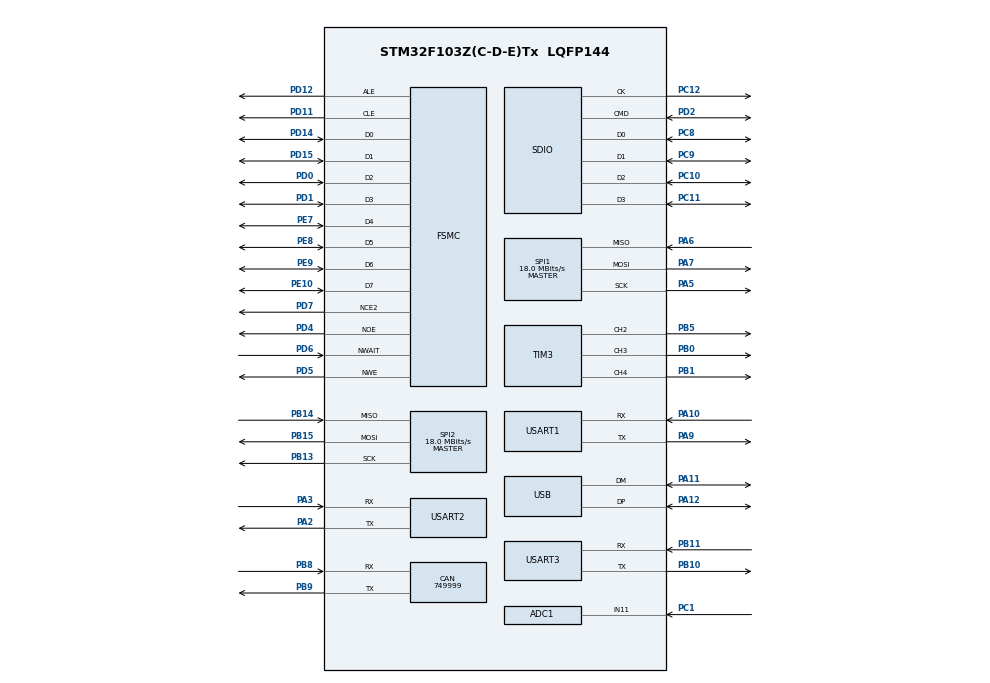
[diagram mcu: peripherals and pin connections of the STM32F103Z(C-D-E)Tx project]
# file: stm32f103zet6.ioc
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ADC1.Channel-0\#ChannelRegularConversion=ADC_CHANNEL_11
ADC1.NbrOfConversionFlag=1
ADC1.Rank-0\#ChannelRegularConversion=1
ADC1.SamplingTime-0\#ChannelRegularConversion=ADC_SAMPLETIME_1CYCLE_5
ADC1.master=1
CAN.CalculateBaudRate=749999
CAN.CalculateTimeBit=1333
CAN.CalculateTimeQuantum=444.44444444444446
FSMC.AttributeSpaceHiZSetupTime1=4
FSMC.AttributeSpaceHoldSetupTime1=2
FSMC.AttributeSpaceSetupTime1=4
FSMC.AttributeSpaceWaitSetupTime1=3
FSMC.CommonSpaceHiZSetupTime1=4
FSMC.CommonSpaceHoldSetupTime1=2
FSMC.CommonSpaceSetupTime1=4
FSMC.CommonSpaceWaitSetupTime1=3
FSMC.ECCPageSize1=FSMC_NAND_ECC_PAGE_SIZE_512BYTE
FSMC.EccComputation1=FSMC_NAND_ECC_ENABLE
FSMC.NandBlockNbr1=1024
FSMC.NandBlockSize1=64
FSMC.NandPageSize1=2048
FSMC.NandPlaneNbr1=1024
FSMC.NandPlaneSize1=1024
FSMC.NandSpareAreaSize1=64
Mcu.Family=STM32F1
Mcu.Name=STM32F103Z(C-D-E)Tx
Mcu.Package=LQFP144
NVIC.PriorityGroup=NVIC_PRIORITYGROUP_4
NVIC.USART1_IRQn=true\:0\:0\:false\:false\:true\:true\:true
OSC_IN.Mode=HSE-External-Oscillator
OSC_IN.Signal=RCC_OSC_IN
OSC_OUT.Mode=HSE-External-Oscillator
OSC_OUT.Signal=RCC_OSC_OUT
PA10.Mode=Asynchronous
PA10.Signal=USART1_RX
PA11.Mode=Device
PA11.Signal=USB_DM
PA12.Mode=Device
PA12.Signal=USB_DP
PA13.Mode=Serial_Wire
PA13.Signal=SYS_JTMS-SWDIO
PA14.Mode=Serial_Wire
PA14.Signal=SYS_JTCK-SWCLK
PA2.Mode=Asynchronous
PA2.Signal=USART2_TX
PA3.Mode=Asynchronous
PA3.Signal=USART2_RX
PA5.Mode=Full_Duplex_Master
PA5.Signal=SPI1_SCK
PA6.Mode=Full_Duplex_Master
PA6.Signal=SPI1_MISO
PA7.Mode=Full_Duplex_Master
PA7.Signal=SPI1_MOSI
PA9.Mode=Asynchronous
PA9.Signal=USART1_TX
PB0.Signal=S_TIM3_CH3
PB1.Signal=S_TIM3_CH4
PB10.Mode=Asynchronous
PB10.Signal=USART3_TX
PB11.Mode=Asynchronous
PB11.Signal=USART3_RX
PB13.Mode=Full_Duplex_Master
PB13.Signal=SPI2_SCK
PB14.Mode=Full_Duplex_Master
PB14.Signal=SPI2_MISO
PB15.Mode=Full_Duplex_Master
PB15.Signal=SPI2_MOSI
PB5.Signal=S_TIM3_CH2
PB8.Mode=CAN_Activate
PB8.Signal=CAN_RX
PB9.Mode=CAN_Activate
PB9.Signal=CAN_TX
PC1.Signal=ADCx_IN11
PC10.Mode=SD_4_bits_Wide_bus
PC10.Signal=SDIO_D2
PC11.Mode=SD_4_bits_Wide_bus
PC11.Signal=SDIO_D3
PC12.Mode=SD_4_bits_Wide_bus
PC12.Signal=SDIO_CK
PC14-OSC32_IN.Mode=LSE-External-Oscillator
PC14-OSC32_IN.Signal=RCC_OSC32_IN
PC15-OSC32_OUT.Mode=LSE-External-Oscillator
PC15-OSC32_OUT.Signal=RCC_OSC32_OUT
PC8.Mode=SD_4_bits_Wide_bus
PC8.Signal=SDIO_D0
PC9.Mode=SD_4_bits_Wide_bus
PC9.Signal=SDIO_D1
PD0.Signal=FSMC_D2_DA2
PD1.Signal=FSMC_D3_DA3
PD11.Signal=FSMC_A16_CLE
PD12.Signal=FSMC_A17_ALE
PD14.Signal=FSMC_D0_DA0
PD15.Signal=FSMC_D1_DA1
PD2.Mode=SD_4_bits_Wide_bus
PD2.Signal=SDIO_CMD
PD4.Signal=FSMC_NOE
PD5.Signal=FSMC_NWE
PD6.Signal=FSMC_NWAIT
PD7.Mode=NandChipSelect2_1
PD7.Signal=FSMC_NCE2
PE10.Signal=FSMC_D7_DA7
PE7.Signal=FSMC_D4_DA4
PE8.Signal=FSMC_D5_DA5
PE9.Signal=FSMC_D6_DA6
ProjectManager.HeapSize=0x200
ProjectManager.StackSize=0x400
ProjectManager.TargetToolchain=MDK-ARM V5
RCC.ADCPresc=RCC_ADCPCLK2_DIV6
RCC.AHBFreq_Value=72000000
RCC.APB1CLKDivider=RCC_HCLK_DIV2
RCC.APB1Freq_Value=36000000
RCC.APB1TimFreq_Value=72000000
RCC.APB2Freq_Value=72000000
RCC.APB2TimFreq_Value=72000000
RCC.HCLKFreq_Value=72000000
RCC.PLLMUL=RCC_PLL_MUL9
RCC.PLLSourceVirtual=RCC_PLLSOURCE_HSE
RCC.SYSCLKFreq_VALUE=72000000
RCC.SYSCLKSource=RCC_SYSCLKSOURCE_PLLCLK
RCC.USBFreq_Value=48000000
RCC.USBPrescaler=RCC_USBCLKSOURCE_PLL_DIV1_5
SH.ADCx_IN11.0=ADC1_IN11,IN11
SH.FSMC_A16_CLE.0=FSMC_CLE,8b-dmux1
SH.FSMC_A17_ALE.0=FSMC_ALE,8b-dmux1
SH.FSMC_D0_DA0.0=FSMC_D0,8b-dmux1
SH.FSMC_D1_DA1.0=FSMC_D1,8b-dmux1
SH.FSMC_D2_DA2.0=FSMC_D2,8b-dmux1
SH.FSMC_D3_DA3.0=FSMC_D3,8b-dmux1
SH.FSMC_D4_DA4.0=FSMC_D4,8b-dmux1
SH.FSMC_D5_DA5.0=FSMC_D5,8b-dmux1
SH.FSMC_D6_DA6.0=FSMC_D6,8b-dmux1
SH.FSMC_D7_DA7.0=FSMC_D7,8b-dmux1
SH.FSMC_NOE.0=FSMC_NOE,8b-dmux1
SH.FSMC_NWAIT.0=FSMC_NWAIT,Wait1
SH.FSMC_NWE.0=FSMC_NWE,8b-dmux1
SH.S_TIM3_CH2.0=TIM3_CH2,PWM Generation2 CH2
SH.S_TIM3_CH3.0=TIM3_CH3,PWM Generation3 CH3
SH.S_TIM3_CH4.0=TIM3_CH4,PWM Generation4 CH4
SPI1.BaudRatePrescaler=SPI_BAUDRATEPRESCALER_4
SPI1.CalculateBaudRate=18.0 MBits/s
SPI1.Direction=SPI_DIRECTION_2LINES
SPI1.Mode=SPI_MODE_MASTER
SPI1.VirtualType=VM_MASTER
SPI2.CalculateBaudRate=18.0 MBits/s
SPI2.Direction=SPI_DIRECTION_2LINES
SPI2.Mode=SPI_MODE_MASTER
SPI2.VirtualType=VM_MASTER
TIM3.Channel-PWM\ Generation2\ CH2=TIM_CHANNEL_2
TIM3.Channel-PWM\ Generation3\ CH3=TIM_CHANNEL_3
TIM3.Channel-PWM\ Generation4\ CH4=TIM_CHANNEL_4
USART1.VirtualMode=VM_ASYNC
USART2.VirtualMode=VM_ASYNC
USART3.VirtualMode=VM_ASYNC
VP_IWDG_VS_IWDG.Mode=IWDG_Activate
VP_RTC_VS_RTC_Activate.Mode=RTC_Enabled
VP_TIM2_VS_ClockSourceINT.Mode=Internal
VP_TIM3_VS_ClockSourceINT.Mode=Internal
VP_TIM4_VS_ClockSourceINT.Mode=Internal
VP_TIM5_VS_ClockSourceINT.Mode=Internal
board=custom

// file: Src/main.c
/* USER CODE BEGIN Header */
/**
  ******************************************************************************
  * @file           : main.c
  * @brief          : Main program body
  ******************************************************************************
  ** This notice applies to any and all portions of this file
  * that are not between comment pairs USER CODE BEGIN and
  * USER CODE END. Other portions of this file, whether
  * inserted by the user or by software development tools
  * are owned by their respective copyright owners.
  *
  * COPYRIGHT(c) 2018 STMicroelectronics
  *
  * Redistribution and use in source and binary forms, with or without modification,
  * are permitted provided that the following conditions are met:
  *   1. Redistributions of source code must retain the above copyright notice,
  *      this list of conditions and the following disclaimer.
  *   2. Redistributions in binary form must reproduce the above copyright notice,
  *      this list of conditions and the following disclaimer in the documentation
  *      and/or other materials provided with the distribution.
  *   3. Neither the name of STMicroelectronics nor the names of its contributors
  *      may be used to endorse or promote products derived from this software
  *      without specific prior written permission.
  *
  * THIS SOFTWARE IS PROVIDED BY THE COPYRIGHT HOLDERS AND CONTRIBUTORS "AS IS"
  * AND ANY EXPRESS OR IMPLIED WARRANTIES, INCLUDING, BUT NOT LIMITED TO, THE
  * IMPLIED WARRANTIES OF MERCHANTABILITY AND FITNESS FOR A PARTICULAR PURPOSE ARE
  * DISCLAIMED. IN NO EVENT SHALL THE COPYRIGHT HOLDER OR CONTRIBUTORS BE LIABLE
  * FOR ANY DIRECT, INDIRECT, INCIDENTAL, SPECIAL, EXEMPLARY, OR CONSEQUENTIAL
  * DAMAGES (INCLUDING, BUT NOT LIMITED TO, PROCUREMENT OF SUBSTITUTE GOODS OR
  * SERVICES; LOSS OF USE, DATA, OR PROFITS; OR BUSINESS INTERRUPTION) HOWEVER
  * CAUSED AND ON ANY THEORY OF LIABILITY, WHETHER IN CONTRACT, STRICT LIABILITY,
  * OR TORT (INCLUDING NEGLIGENCE OR OTHERWISE) ARISING IN ANY WAY OUT OF THE USE
  * OF THIS SOFTWARE, EVEN IF ADVISED OF THE POSSIBILITY OF SUCH DAMAGE.
  *
  ******************************************************************************
  */
/* USER CODE END Header */

#include "main.h"

ADC_HandleTypeDef hadc1;

CAN_HandleTypeDef hcan;

IWDG_HandleTypeDef hiwdg;

RTC_HandleTypeDef hrtc;

SD_HandleTypeDef hsd;

SPI_HandleTypeDef hspi1;
SPI_HandleTypeDef hspi2;

TIM_HandleTypeDef htim2;
TIM_HandleTypeDef htim3;
TIM_HandleTypeDef htim4;
TIM_HandleTypeDef htim5;

UART_HandleTypeDef huart1;
UART_HandleTypeDef huart2;
UART_HandleTypeDef huart3;

PCD_HandleTypeDef hpcd_USB_FS;

/* USER CODE BEGIN PV */
/* Private variables ---------------------------------------------------------*/

/* USER CODE END PV */

void SystemClock_Config(void);
static void MX_GPIO_Init(void);
static void MX_USART1_UART_Init(void);
static void MX_SPI2_Init(void);
static void MX_USART2_UART_Init(void);
static void MX_SPI1_Init(void);
static void MX_USART3_UART_Init(void);
static void MX_ADC1_Init(void);
static void MX_RTC_Init(void);
static void MX_IWDG_Init(void);
static void MX_TIM2_Init(void);
static void MX_TIM3_Init(void);
static void MX_TIM4_Init(void);
static void MX_TIM5_Init(void);
static void MX_SDIO_SD_Init(void);
static void MX_CAN_Init(void);
static void MX_USB_PCD_Init(void);
/* USER CODE BEGIN PFP */
/* Private function prototypes -----------------------------------------------*/

/* USER CODE END PFP */

int main(void)
{

  /* MCU Configuration--------------------------------------------------------*/

  /* Reset of all peripherals, Initializes the Flash interface and the Systick. */
  HAL_Init();

  /* Configure the system clock */
  SystemClock_Config();

  /* Initialize all configured peripherals */
  MX_GPIO_Init();
  MX_USART1_UART_Init();
  MX_SPI2_Init();
  MX_USART2_UART_Init();
  MX_SPI1_Init();
  MX_USART3_UART_Init();
  MX_ADC1_Init();
  MX_RTC_Init();
  MX_IWDG_Init();
  MX_TIM2_Init();
  MX_TIM3_Init();
  MX_TIM4_Init();
  MX_TIM5_Init();
  MX_SDIO_SD_Init();
  MX_CAN_Init();
  MX_USB_PCD_Init();

  /* Infinite loop */
  while (1)
  {

  }
}

void SystemClock_Config(void)
{
  RCC_OscInitTypeDef RCC_OscInitStruct = {0};
  RCC_ClkInitTypeDef RCC_ClkInitStruct = {0};
  RCC_PeriphCLKInitTypeDef PeriphClkInit = {0};

  /** Initializes the CPU, AHB and APB busses clocks
  */
  RCC_OscInitStruct.OscillatorType = RCC_OSCILLATORTYPE_LSI|RCC_OSCILLATORTYPE_HSE
                              |RCC_OSCILLATORTYPE_LSE;
  RCC_OscInitStruct.HSEState = RCC_HSE_ON;
  RCC_OscInitStruct.HSEPredivValue = RCC_HSE_PREDIV_DIV1;
  RCC_OscInitStruct.LSEState = RCC_LSE_ON;
  RCC_OscInitStruct.HSIState = RCC_HSI_ON;
  RCC_OscInitStruct.LSIState = RCC_LSI_ON;
  RCC_OscInitStruct.PLL.PLLState = RCC_PLL_ON;
  RCC_OscInitStruct.PLL.PLLSource = RCC_PLLSOURCE_HSE;
  RCC_OscInitStruct.PLL.PLLMUL = RCC_PLL_MUL6;
  if (HAL_RCC_OscConfig(&RCC_OscInitStruct) != HAL_OK)
  {
    Error_Handler();
  }
  /** Initializes the CPU, AHB and APB busses clocks
  */
  RCC_ClkInitStruct.ClockType = RCC_CLOCKTYPE_HCLK|RCC_CLOCKTYPE_SYSCLK
                              |RCC_CLOCKTYPE_PCLK1|RCC_CLOCKTYPE_PCLK2;
  RCC_ClkInitStruct.SYSCLKSource = RCC_SYSCLKSOURCE_PLLCLK;
  RCC_ClkInitStruct.AHBCLKDivider = RCC_SYSCLK_DIV1;
  RCC_ClkInitStruct.APB1CLKDivider = RCC_HCLK_DIV2;
  RCC_ClkInitStruct.APB2CLKDivider = RCC_HCLK_DIV1;

  if (HAL_RCC_ClockConfig(&RCC_ClkInitStruct, FLASH_LATENCY_1) != HAL_OK)
  {
    Error_Handler();
  }
  PeriphClkInit.PeriphClockSelection = RCC_PERIPHCLK_RTC|RCC_PERIPHCLK_ADC
                              |RCC_PERIPHCLK_USB;
  PeriphClkInit.RTCClockSelection = RCC_RTCCLKSOURCE_LSE;
  PeriphClkInit.AdcClockSelection = RCC_ADCPCLK2_DIV4;
  PeriphClkInit.UsbClockSelection = RCC_USBCLKSOURCE_PLL;
  if (HAL_RCCEx_PeriphCLKConfig(&PeriphClkInit) != HAL_OK)
  {
    Error_Handler();
  }
}

static void MX_ADC1_Init(void)
{

  ADC_ChannelConfTypeDef sConfig = {0};

  /** Common config
  */
  hadc1.Instance = ADC1;
  hadc1.Init.ScanConvMode = ADC_SCAN_DISABLE;
  hadc1.Init.ContinuousConvMode = DISABLE;
  hadc1.Init.DiscontinuousConvMode = DISABLE;
  hadc1.Init.ExternalTrigConv = ADC_SOFTWARE_START;
  hadc1.Init.DataAlign = ADC_DATAALIGN_RIGHT;
  hadc1.Init.NbrOfConversion = 1;
  if (HAL_ADC_Init(&hadc1) != HAL_OK)
  {
    Error_Handler();
  }
  /** Configure Regular Channel
  */
  sConfig.Channel = ADC_CHANNEL_11;
  sConfig.Rank = ADC_REGULAR_RANK_1;
  sConfig.SamplingTime = ADC_SAMPLETIME_1CYCLE_5;
  if (HAL_ADC_ConfigChannel(&hadc1, &sConfig) != HAL_OK)
  {
    Error_Handler();
  }

}

static void MX_CAN_Init(void)
{

  hcan.Instance = CAN1;
  hcan.Init.Prescaler = 16;
  hcan.Init.Mode = CAN_MODE_NORMAL;
  hcan.Init.SyncJumpWidth = CAN_SJW_1TQ;
  hcan.Init.TimeSeg1 = CAN_BS1_1TQ;
  hcan.Init.TimeSeg2 = CAN_BS2_1TQ;
  hcan.Init.TimeTriggeredMode = DISABLE;
  hcan.Init.AutoBusOff = DISABLE;
  hcan.Init.AutoWakeUp = DISABLE;
  hcan.Init.AutoRetransmission = DISABLE;
  hcan.Init.ReceiveFifoLocked = DISABLE;
  hcan.Init.TransmitFifoPriority = DISABLE;
  if (HAL_CAN_Init(&hcan) != HAL_OK)
  {
    Error_Handler();
  }

}

static void MX_IWDG_Init(void)
{

  hiwdg.Instance = IWDG;
  hiwdg.Init.Prescaler = IWDG_PRESCALER_4;
  hiwdg.Init.Reload = 4095;
  if (HAL_IWDG_Init(&hiwdg) != HAL_OK)
  {
    Error_Handler();
  }

}

static void MX_RTC_Init(void)
{

  /** Initialize RTC Only
  */
  hrtc.Instance = RTC;
  hrtc.Init.AsynchPrediv = RTC_AUTO_1_SECOND;
  hrtc.Init.OutPut = RTC_OUTPUTSOURCE_ALARM;
  if (HAL_RTC_Init(&hrtc) != HAL_OK)
  {
    Error_Handler();
  }

}

static void MX_SDIO_SD_Init(void)
{

  hsd.Instance = SDIO;
  hsd.Init.ClockEdge = SDIO_CLOCK_EDGE_RISING;
  hsd.Init.ClockBypass = SDIO_CLOCK_BYPASS_DISABLE;
  hsd.Init.ClockPowerSave = SDIO_CLOCK_POWER_SAVE_DISABLE;
  hsd.Init.BusWide = SDIO_BUS_WIDE_1B;
  hsd.Init.HardwareFlowControl = SDIO_HARDWARE_FLOW_CONTROL_DISABLE;
  hsd.Init.ClockDiv = 0;
  if (HAL_SD_Init(&hsd) != HAL_OK)
  {
    Error_Handler();
  }
  if (HAL_SD_ConfigWideBusOperation(&hsd, SDIO_BUS_WIDE_4B) != HAL_OK)
  {
    Error_Handler();
  }

}

static void MX_SPI1_Init(void)
{

  /* SPI1 parameter configuration*/
  hspi1.Instance = SPI1;
  hspi1.Init.Mode = SPI_MODE_MASTER;
  hspi1.Init.Direction = SPI_DIRECTION_2LINES;
  hspi1.Init.DataSize = SPI_DATASIZE_8BIT;
  hspi1.Init.CLKPolarity = SPI_POLARITY_LOW;
  hspi1.Init.CLKPhase = SPI_PHASE_1EDGE;
  hspi1.Init.NSS = SPI_NSS_SOFT;
  hspi1.Init.BaudRatePrescaler = SPI_BAUDRATEPRESCALER_4;
  hspi1.Init.FirstBit = SPI_FIRSTBIT_MSB;
  hspi1.Init.TIMode = SPI_TIMODE_DISABLE;
  hspi1.Init.CRCCalculation = SPI_CRCCALCULATION_DISABLE;
  hspi1.Init.CRCPolynomial = 10;
  if (HAL_SPI_Init(&hspi1) != HAL_OK)
  {
    Error_Handler();
  }

}

static void MX_SPI2_Init(void)
{

  /* SPI2 parameter configuration*/
  hspi2.Instance = SPI2;
  hspi2.Init.Mode = SPI_MODE_MASTER;
  hspi2.Init.Direction = SPI_DIRECTION_2LINES;
  hspi2.Init.DataSize = SPI_DATASIZE_8BIT;
  hspi2.Init.CLKPolarity = SPI_POLARITY_LOW;
  hspi2.Init.CLKPhase = SPI_PHASE_1EDGE;
  hspi2.Init.NSS = SPI_NSS_SOFT;
  hspi2.Init.BaudRatePrescaler = SPI_BAUDRATEPRESCALER_2;
  hspi2.Init.FirstBit = SPI_FIRSTBIT_MSB;
  hspi2.Init.TIMode = SPI_TIMODE_DISABLE;
  hspi2.Init.CRCCalculation = SPI_CRCCALCULATION_DISABLE;
  hspi2.Init.CRCPolynomial = 10;
  if (HAL_SPI_Init(&hspi2) != HAL_OK)
  {
    Error_Handler();
  }

}

static void MX_TIM2_Init(void)
{

  TIM_ClockConfigTypeDef sClockSourceConfig = {0};
  TIM_MasterConfigTypeDef sMasterConfig = {0};

  htim2.Instance = TIM2;
  htim2.Init.Prescaler = 0;
  htim2.Init.CounterMode = TIM_COUNTERMODE_UP;
  htim2.Init.Period = 0;
  htim2.Init.ClockDivision = TIM_CLOCKDIVISION_DIV1;
  htim2.Init.AutoReloadPreload = TIM_AUTORELOAD_PRELOAD_DISABLE;
  if (HAL_TIM_Base_Init(&htim2) != HAL_OK)
  {
    Error_Handler();
  }
  sClockSourceConfig.ClockSource = TIM_CLOCKSOURCE_INTERNAL;
  if (HAL_TIM_ConfigClockSource(&htim2, &sClockSourceConfig) != HAL_OK)
  {
    Error_Handler();
  }
  sMasterConfig.MasterOutputTrigger = TIM_TRGO_RESET;
  sMasterConfig.MasterSlaveMode = TIM_MASTERSLAVEMODE_DISABLE;
  if (HAL_TIMEx_MasterConfigSynchronization(&htim2, &sMasterConfig) != HAL_OK)
  {
    Error_Handler();
  }

}

static void MX_TIM3_Init(void)
{

  TIM_ClockConfigTypeDef sClockSourceConfig = {0};
  TIM_MasterConfigTypeDef sMasterConfig = {0};
  TIM_OC_InitTypeDef sConfigOC = {0};

  htim3.Instance = TIM3;
  htim3.Init.Prescaler = 0;
  htim3.Init.CounterMode = TIM_COUNTERMODE_UP;
  htim3.Init.Period = 0;
  htim3.Init.ClockDivision = TIM_CLOCKDIVISION_DIV1;
  htim3.Init.AutoReloadPreload = TIM_AUTORELOAD_PRELOAD_DISABLE;
  if (HAL_TIM_Base_Init(&htim3) != HAL_OK)
  {
    Error_Handler();
  }
  sClockSourceConfig.ClockSource = TIM_CLOCKSOURCE_INTERNAL;
  if (HAL_TIM_ConfigClockSource(&htim3, &sClockSourceConfig) != HAL_OK)
  {
    Error_Handler();
  }
  if (HAL_TIM_PWM_Init(&htim3) != HAL_OK)
  {
    Error_Handler();
  }
  sMasterConfig.MasterOutputTrigger = TIM_TRGO_RESET;
  sMasterConfig.MasterSlaveMode = TIM_MASTERSLAVEMODE_DISABLE;
  if (HAL_TIMEx_MasterConfigSynchronization(&htim3, &sMasterConfig) != HAL_OK)
  {
    Error_Handler();
  }
  sConfigOC.OCMode = TIM_OCMODE_PWM1;
  sConfigOC.Pulse = 0;
  sConfigOC.OCPolarity = TIM_OCPOLARITY_HIGH;
  sConfigOC.OCFastMode = TIM_OCFAST_DISABLE;
  if (HAL_TIM_PWM_ConfigChannel(&htim3, &sConfigOC, TIM_CHANNEL_2) != HAL_OK)
  {
    Error_Handler();
  }
  if (HAL_TIM_PWM_ConfigChannel(&htim3, &sConfigOC, TIM_CHANNEL_3) != HAL_OK)
  {
    Error_Handler();
  }
  if (HAL_TIM_PWM_ConfigChannel(&htim3, &sConfigOC, TIM_CHANNEL_4) != HAL_OK)
  {
    Error_Handler();
  }
  HAL_TIM_MspPostInit(&htim3);

}

static void MX_TIM4_Init(void)
{

  TIM_ClockConfigTypeDef sClockSourceConfig = {0};
  TIM_MasterConfigTypeDef sMasterConfig = {0};

  htim4.Instance = TIM4;
  htim4.Init.Prescaler = 0;
  htim4.Init.CounterMode = TIM_COUNTERMODE_UP;
  htim4.Init.Period = 0;
  htim4.Init.ClockDivision = TIM_CLOCKDIVISION_DIV1;
  htim4.Init.AutoReloadPreload = TIM_AUTORELOAD_PRELOAD_DISABLE;
  if (HAL_TIM_Base_Init(&htim4) != HAL_OK)
  {
    Error_Handler();
  }
  sClockSourceConfig.ClockSource = TIM_CLOCKSOURCE_INTERNAL;
  if (HAL_TIM_ConfigClockSource(&htim4, &sClockSourceConfig) != HAL_OK)
  {
    Error_Handler();
  }
  sMasterConfig.MasterOutputTrigger = TIM_TRGO_RESET;
  sMasterConfig.MasterSlaveMode = TIM_MASTERSLAVEMODE_DISABLE;
  if (HAL_TIMEx_MasterConfigSynchronization(&htim4, &sMasterConfig) != HAL_OK)
  {
    Error_Handler();
  }

}

static void MX_TIM5_Init(void)
{

  TIM_ClockConfigTypeDef sClockSourceConfig = {0};
  TIM_MasterConfigTypeDef sMasterConfig = {0};

  htim5.Instance = TIM5;
  htim5.Init.Prescaler = 0;
  htim5.Init.CounterMode = TIM_COUNTERMODE_UP;
  htim5.Init.Period = 0;
  htim5.Init.ClockDivision = TIM_CLOCKDIVISION_DIV1;
  htim5.Init.AutoReloadPreload = TIM_AUTORELOAD_PRELOAD_DISABLE;
  if (HAL_TIM_Base_Init(&htim5) != HAL_OK)
  {
    Error_Handler();
  }
  sClockSourceConfig.ClockSource = TIM_CLOCKSOURCE_INTERNAL;
  if (HAL_TIM_ConfigClockSource(&htim5, &sClockSourceConfig) != HAL_OK)
  {
    Error_Handler();
  }
  sMasterConfig.MasterOutputTrigger = TIM_TRGO_RESET;
  sMasterConfig.MasterSlaveMode = TIM_MASTERSLAVEMODE_DISABLE;
  if (HAL_TIMEx_MasterConfigSynchronization(&htim5, &sMasterConfig) != HAL_OK)
  {
    Error_Handler();
  }

}

static void MX_USART1_UART_Init(void)
{

  huart1.Instance = USART1;
  huart1.Init.BaudRate = 115200;
  huart1.Init.WordLength = UART_WORDLENGTH_8B;
  huart1.Init.StopBits = UART_STOPBITS_1;
  huart1.Init.Parity = UART_PARITY_NONE;
  huart1.Init.Mode = UART_MODE_TX_RX;
  huart1.Init.HwFlowCtl = UART_HWCONTROL_NONE;
  huart1.Init.OverSampling = UART_OVERSAMPLING_16;
  if (HAL_UART_Init(&huart1) != HAL_OK)
  {
    Error_Handler();
  }

}

static void MX_USART2_UART_Init(void)
{

  huart2.Instance = USART2;
  huart2.Init.BaudRate = 115200;
  huart2.Init.WordLength = UART_WORDLENGTH_8B;
  huart2.Init.StopBits = UART_STOPBITS_1;
  huart2.Init.Parity = UART_PARITY_NONE;
  huart2.Init.Mode = UART_MODE_TX_RX;
  huart2.Init.HwFlowCtl = UART_HWCONTROL_NONE;
  huart2.Init.OverSampling = UART_OVERSAMPLING_16;
  if (HAL_UART_Init(&huart2) != HAL_OK)
  {
    Error_Handler();
  }

}

static void MX_USART3_UART_Init(void)
{

  huart3.Instance = USART3;
  huart3.Init.BaudRate = 115200;
  huart3.Init.WordLength = UART_WORDLENGTH_8B;
  huart3.Init.StopBits = UART_STOPBITS_1;
  huart3.Init.Parity = UART_PARITY_NONE;
  huart3.Init.Mode = UART_MODE_TX_RX;
  huart3.Init.HwFlowCtl = UART_HWCONTROL_NONE;
  huart3.Init.OverSampling = UART_OVERSAMPLING_16;
  if (HAL_UART_Init(&huart3) != HAL_OK)
  {
    Error_Handler();
  }

}

static void MX_USB_PCD_Init(void)
{

  hpcd_USB_FS.Instance = USB;
  hpcd_USB_FS.Init.dev_endpoints = 8;
  hpcd_USB_FS.Init.speed = PCD_SPEED_FULL;
  hpcd_USB_FS.Init.low_power_enable = DISABLE;
  hpcd_USB_FS.Init.lpm_enable = DISABLE;
  hpcd_USB_FS.Init.battery_charging_enable = DISABLE;
  if (HAL_PCD_Init(&hpcd_USB_FS) != HAL_OK)
  {
    Error_Handler();
  }

}

static void MX_GPIO_Init(void)
{

  /* GPIO Ports Clock Enable */
  __HAL_RCC_GPIOC_CLK_ENABLE();
  __HAL_RCC_GPIOA_CLK_ENABLE();
  __HAL_RCC_GPIOB_CLK_ENABLE();
  __HAL_RCC_GPIOD_CLK_ENABLE();

}

void Error_Handler(void)
{
  while(1)
  {
  }
}

/************************ (C) COPYRIGHT STMicroelectronics *****END OF FILE****/
